One B-rep face of a CAD part: STEP entity #566.
In plain terms, the planar face has unit normal (0, -1, 0).
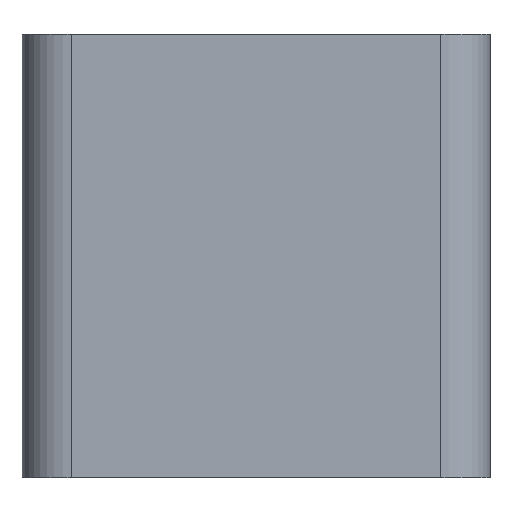
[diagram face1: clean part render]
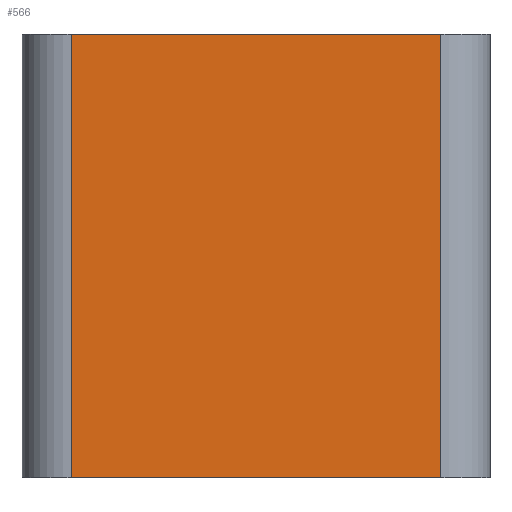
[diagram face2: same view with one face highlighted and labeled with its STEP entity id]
Its self-contained STEP definition (entity closure, numbers rounded to 3 decimals):
#44 = PLANE('',#45);
#45 = AXIS2_PLACEMENT_3D('',#46,#47,#48);
#46 = CARTESIAN_POINT('',(-12.226,-29.4,2.));
#47 = DIRECTION('',(0.,-0.,-1.));
#48 = DIRECTION('',(-1.,0.,0.));
#72 = CYLINDRICAL_SURFACE('',#73,0.4);
#73 = AXIS2_PLACEMENT_3D('',#74,#75,#76);
#74 = CARTESIAN_POINT('',(-11.826,-29.,5.6));
#75 = DIRECTION('',(-0.,-0.,-1.));
#76 = DIRECTION('',(-1.,-0.,-0.));
#100 = PLANE('',#101);
#101 = AXIS2_PLACEMENT_3D('',#102,#103,#104);
#102 = CARTESIAN_POINT('',(-12.226,-29.4,5.6));
#103 = DIRECTION('',(0.,-0.,-1.));
#104 = DIRECTION('',(-1.,0.,0.));
#143 = VERTEX_POINT('',#144);
#144 = CARTESIAN_POINT('',(-11.826,-29.4,2.));
#170 = EDGE_CURVE('',#143,#171,#173,.T.);
#171 = VERTEX_POINT('',#172);
#172 = CARTESIAN_POINT('',(-8.826,-29.4,2.));
#173 = SURFACE_CURVE('',#174,(#178,#185),.PCURVE_S1.);
#174 = LINE('',#175,#176);
#175 = CARTESIAN_POINT('',(-12.226,-29.4,2.));
#176 = VECTOR('',#177,1.);
#177 = DIRECTION('',(1.,0.,-0.));
#178 = PCURVE('',#44,#179);
#179 = DEFINITIONAL_REPRESENTATION('',(#180),#184);
#180 = LINE('',#181,#182);
#181 = CARTESIAN_POINT('',(-0.,0.));
#182 = VECTOR('',#183,1.);
#183 = DIRECTION('',(-1.,0.));
#184 = ( GEOMETRIC_REPRESENTATION_CONTEXT(2) 
PARAMETRIC_REPRESENTATION_CONTEXT() REPRESENTATION_CONTEXT('2D SPACE',''
  ) );
#185 = PCURVE('',#186,#191);
#186 = PLANE('',#187);
#187 = AXIS2_PLACEMENT_3D('',#188,#189,#190);
#188 = CARTESIAN_POINT('',(-12.226,-29.4,5.6));
#189 = DIRECTION('',(-0.,1.,0.));
#190 = DIRECTION('',(0.,0.,1.));
#191 = DEFINITIONAL_REPRESENTATION('',(#192),#196);
#192 = LINE('',#193,#194);
#193 = CARTESIAN_POINT('',(-3.6,0.));
#194 = VECTOR('',#195,1.);
#195 = DIRECTION('',(-0.,1.));
#196 = ( GEOMETRIC_REPRESENTATION_CONTEXT(2) 
PARAMETRIC_REPRESENTATION_CONTEXT() REPRESENTATION_CONTEXT('2D SPACE',''
  ) );
#215 = CYLINDRICAL_SURFACE('',#216,0.4);
#216 = AXIS2_PLACEMENT_3D('',#217,#218,#219);
#217 = CARTESIAN_POINT('',(-8.826,-29.,5.6));
#218 = DIRECTION('',(-0.,-0.,-1.));
#219 = DIRECTION('',(1.,-0.,-0.));
#342 = VERTEX_POINT('',#343);
#343 = CARTESIAN_POINT('',(-11.826,-29.4,5.6));
#369 = EDGE_CURVE('',#342,#143,#370,.T.);
#370 = SURFACE_CURVE('',#371,(#375,#382),.PCURVE_S1.);
#371 = LINE('',#372,#373);
#372 = CARTESIAN_POINT('',(-11.826,-29.4,5.6));
#373 = VECTOR('',#374,1.);
#374 = DIRECTION('',(-0.,-0.,-1.));
#375 = PCURVE('',#72,#376);
#376 = DEFINITIONAL_REPRESENTATION('',(#377),#381);
#377 = LINE('',#378,#379);
#378 = CARTESIAN_POINT('',(-1.571,0.));
#379 = VECTOR('',#380,1.);
#380 = DIRECTION('',(-0.,1.));
#381 = ( GEOMETRIC_REPRESENTATION_CONTEXT(2) 
PARAMETRIC_REPRESENTATION_CONTEXT() REPRESENTATION_CONTEXT('2D SPACE',''
  ) );
#382 = PCURVE('',#186,#383);
#383 = DEFINITIONAL_REPRESENTATION('',(#384),#388);
#384 = LINE('',#385,#386);
#385 = CARTESIAN_POINT('',(0.,0.4));
#386 = VECTOR('',#387,1.);
#387 = DIRECTION('',(-1.,0.));
#388 = ( GEOMETRIC_REPRESENTATION_CONTEXT(2) 
PARAMETRIC_REPRESENTATION_CONTEXT() REPRESENTATION_CONTEXT('2D SPACE',''
  ) );
#447 = EDGE_CURVE('',#342,#448,#450,.T.);
#448 = VERTEX_POINT('',#449);
#449 = CARTESIAN_POINT('',(-8.826,-29.4,5.6));
#450 = SURFACE_CURVE('',#451,(#455,#462),.PCURVE_S1.);
#451 = LINE('',#452,#453);
#452 = CARTESIAN_POINT('',(-12.226,-29.4,5.6));
#453 = VECTOR('',#454,1.);
#454 = DIRECTION('',(1.,0.,-0.));
#455 = PCURVE('',#100,#456);
#456 = DEFINITIONAL_REPRESENTATION('',(#457),#461);
#457 = LINE('',#458,#459);
#458 = CARTESIAN_POINT('',(-0.,0.));
#459 = VECTOR('',#460,1.);
#460 = DIRECTION('',(-1.,0.));
#461 = ( GEOMETRIC_REPRESENTATION_CONTEXT(2) 
PARAMETRIC_REPRESENTATION_CONTEXT() REPRESENTATION_CONTEXT('2D SPACE',''
  ) );
#462 = PCURVE('',#186,#463);
#463 = DEFINITIONAL_REPRESENTATION('',(#464),#468);
#464 = LINE('',#465,#466);
#465 = CARTESIAN_POINT('',(0.,-0.));
#466 = VECTOR('',#467,1.);
#467 = DIRECTION('',(-0.,1.));
#468 = ( GEOMETRIC_REPRESENTATION_CONTEXT(2) 
PARAMETRIC_REPRESENTATION_CONTEXT() REPRESENTATION_CONTEXT('2D SPACE',''
  ) );
#566 = ADVANCED_FACE('',(#567),#186,.F.);
#567 = FACE_BOUND('',#568,.T.);
#568 = EDGE_LOOP('',(#569,#570,#571,#572));
#569 = ORIENTED_EDGE('',*,*,#447,.F.);
#570 = ORIENTED_EDGE('',*,*,#369,.T.);
#571 = ORIENTED_EDGE('',*,*,#170,.T.);
#572 = ORIENTED_EDGE('',*,*,#573,.F.);
#573 = EDGE_CURVE('',#448,#171,#574,.T.);
#574 = SURFACE_CURVE('',#575,(#579,#586),.PCURVE_S1.);
#575 = LINE('',#576,#577);
#576 = CARTESIAN_POINT('',(-8.826,-29.4,5.6));
#577 = VECTOR('',#578,1.);
#578 = DIRECTION('',(-0.,-0.,-1.));
#579 = PCURVE('',#186,#580);
#580 = DEFINITIONAL_REPRESENTATION('',(#581),#585);
#581 = LINE('',#582,#583);
#582 = CARTESIAN_POINT('',(0.,3.4));
#583 = VECTOR('',#584,1.);
#584 = DIRECTION('',(-1.,0.));
#585 = ( GEOMETRIC_REPRESENTATION_CONTEXT(2) 
PARAMETRIC_REPRESENTATION_CONTEXT() REPRESENTATION_CONTEXT('2D SPACE',''
  ) );
#586 = PCURVE('',#215,#587);
#587 = DEFINITIONAL_REPRESENTATION('',(#588),#592);
#588 = LINE('',#589,#590);
#589 = CARTESIAN_POINT('',(1.571,0.));
#590 = VECTOR('',#591,1.);
#591 = DIRECTION('',(0.,1.));
#592 = ( GEOMETRIC_REPRESENTATION_CONTEXT(2) 
PARAMETRIC_REPRESENTATION_CONTEXT() REPRESENTATION_CONTEXT('2D SPACE',''
  ) );
